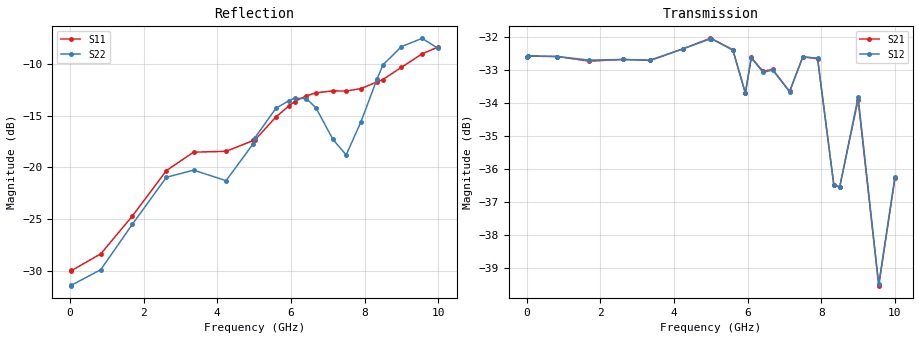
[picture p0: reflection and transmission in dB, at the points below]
! Integrated Device Technology
! Corporate Headquarters
! 6024 Silver Creek Valley Road
! San Jose, CA 95138  USA
! Phone:  1-408-284-8200
! Toll Free:  1-800-223-1366
! Webpage:  http://www.idt.com/
! Timing and RF Division
! 515 Groton Road, Suite 102
! Westford, MA 01886-6024
! Device:  F1958
! Description: 7-bit 0.25 dB Digital Step Attenuator
! Frequency:  0.001 -  6.000 GHz
! Package:  4x4 mm Thin QFN Plastic Package: 24 pin
! Ports:  2 RF, 12 DC
!  Pin  1  = D0
!  Pin  2  = VDD
!  Pin  3  = VMODE
!  Pin  4  = GND
!  Pin  5  = RF1  =  Port 1
!  Pin  6  = GND
!  Pin  7  = GND
!  Pin  8  = GND
!  Pin  9  = GND
!  Pin 10  = GND
!  Pin 11  = GND
!  Pin 12  = GND
!  Pin 13  = GND
!  Pin 14  = RF2  =  Port 2
!  Pin 15  = GND
!  Pin 16  = LE
!  Pin 17  = CLK
!  Pin 18  = DATA
!  Pin 19  = D6
!  Pin 20  = D5
!  Pin 21  = D4
!  Pin 22  = D3
!  Pin 23  = D2
!  Pin 24  = D1
! State:  127
! Atten State:  31.75 dB
! Voltage:  +3.30 Volts
! Current:  0.258 mA
! Data:  The device was measured on a F1958 evaluation board which has
!  individual transmission lines to the RF pins.  Data was collected
!  using a calibrated network analyzer.  The evaluation board was
!  de-embedded using Automatic Fixture Removal (AFR).
!  The reference plane is the edge of the package pin.
! Misc:
!  Action Tracker AT0419
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# GHz S dB R 50
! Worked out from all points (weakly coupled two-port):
!   500 points, 20 MHz to 10 GHz, reference 50 ohm
!   highest |S21| = -32.03 dB at 4.98 GHz (marker M1); lowest = -39.5 dB at 9.56 GHz (marker M2)
!   lowest |S11| = -30.0 dB at 40 MHz (marker M3), VSWR 1.07, Z = 46.9 - j0.0449 ohm
!   |S11| at or under -10 dB: start of sweep to 9.126 GHz
!   |S22| runs from -31.7 to -7.4 dB; largest |S21 - S12| = 0.00028
!   S11 on the Smith chart (normalised r, x): 20 MHz: 0.94, -0.00; 6.42 GHz: 0.67, +0.17; 10 GHz: 0.67, +0.59
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0.02  -29.98 -178.9  -32.59 -0.1  -32.58 0.0  -31.46 -178.9
0.04  -30.01 -179.1  -32.57 -0.2  -32.56 -0.1  -31.42 -178.5
0.84  -28.38 171.3  -32.58 -8.5  -32.58 -8.4  -29.91 172.7
1.7  -24.71 171.2  -32.72 -16.6  -32.69 -16.7  -25.50 171.4
2.62  -20.32 177.0  -32.67 -25.6  -32.67 -25.6  -20.97 -179.9
3.36  -18.54 -175.8  -32.70 -33.4  -32.69 -33.6  -20.28 -170.2
4.24  -18.46 -179.2  -32.35 -42.0  -32.35 -42.1  -21.30 168.1
4.98  -17.41 161.7  -32.03 -50.7  -32.05 -50.8  -17.71 137.5
5.02  -17.38 160.7  -32.04 -51.6  -32.04 -51.7  -17.16 138.0
5.6  -15.11 150.8  -32.37 -60.0  -32.39 -60.1  -14.27 139.8
5.94  -14.09 148.3  -33.69 -62.8  -33.69 -62.7  -13.58 148.0
6.1  -13.65 148.5  -32.61 -62.5  -32.62 -62.5  -13.31 149.8
6.42  -13.09 147.6  -33.03 -68.1  -33.06 -68.1  -13.36 156.4
6.68  -12.80 146.7  -32.97 -70.3  -32.99 -70.2  -14.25 156.8
7.14  -12.61 142.8  -33.64 -74.5  -33.65 -74.3  -17.30 150.7
7.5  -12.63 138.3  -32.59 -78.2  -32.59 -77.9  -18.81 118.7
7.9  -12.39 129.0  -32.65 -95.4  -32.63 -95.6  -15.61 88.7
8.34  -11.74 119.0  -36.47 -98.9  -36.47 -99.0  -11.44 83.6
8.5  -11.51 115.6  -36.53 -88.5  -36.55 -88.6  -10.09 87.3
9  -10.33 108.7  -33.89 -97.9  -33.81 -98.0  -8.33 97.2
9.56  -9.03 101.8  -39.53 -93.4  -39.49 -93.2  -7.53 108.4
10  -8.36 99.9  -36.27 -70.3  -36.23 -70.2  -8.51 113.6
